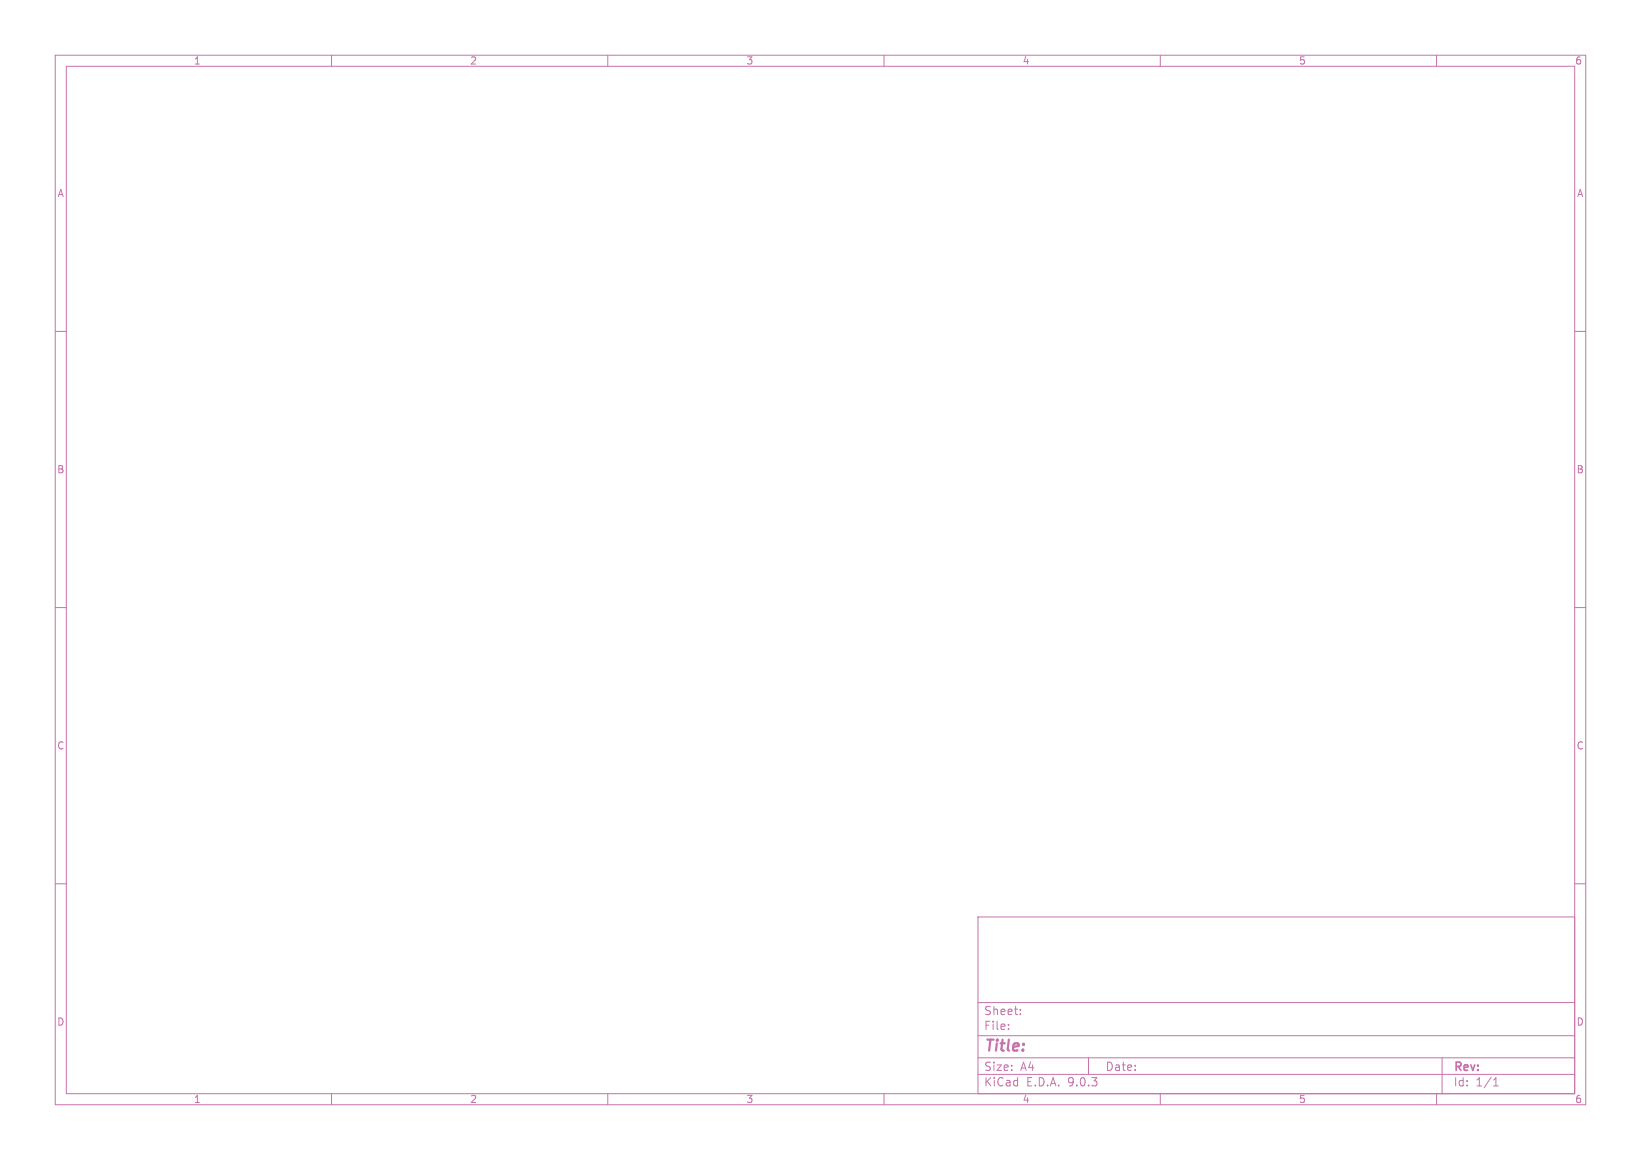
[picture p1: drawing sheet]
<svg xmlns="http://www.w3.org/2000/svg" width="297mm" height="210mm" viewBox="0 0 297 210" stroke-linecap="round" stroke-linejoin="round" font-family="sans-serif">
<defs><g id="words">
<text font-size="2.8" fill="#c872ab" x="178" y="190.9">Title:</text>
<g font-size="2.1" fill="#c872ab">
<text x="178" y="184">Sheet:</text>
<text x="178" y="186.7">File:</text>
<text x="178" y="196.9">KiCad</text>
<text x="178" y="194.1">Size:</text>
<text x="184.7" y="194.1">A4</text>
<text x="185.7" y="196.9">E.D.A.</text>
<text x="193.3" y="196.9">9.0.3</text>
<text x="200" y="194.1">Date:</text>
<text x="263" y="194.3">Rev:</text>
<text x="263" y="196.9">Id:</text>
<text x="267.1" y="196.9">1/1</text>
</g>
<g font-size="1.8" fill="#c872ab">
<text x="35" y="11.9">1</text>
<text x="85" y="11.9">2</text>
<text x="135" y="11.9">3</text>
<text x="185" y="11.9">4</text>
<text x="235" y="11.9">5</text>
<text x="285" y="11.9">6</text>
<text x="10.3" y="35.9">A</text>
<text x="285.4" y="35.9">A</text>
<text x="10.3" y="85.9">B</text>
<text x="285.3" y="85.9">B</text>
<text x="10.3" y="135.9">C</text>
<text x="285.3" y="135.9">C</text>
<text x="10.3" y="185.9">D</text>
<text x="285.3" y="185.9">D</text>
<text x="35" y="199.9">1</text>
<text x="85" y="199.9">2</text>
<text x="135" y="199.9">3</text>
<text x="185" y="199.9">4</text>
<text x="235" y="199.9">5</text>
<text x="285" y="199.9">6</text>
</g>
</g></defs>
<g fill="none" stroke="#c872ab" stroke-width=".18">
<path d="M10 10h277v190h-277zM12 12h273v186h-273zM60 10v2M110 10v2M160 10v2M210 10v2M260 10v2M10 60h2M285 60h2M10 110h2M285 110h2M10 160h2"/>
<path d="M177 166h108v32h-108zM285 160h2M60 198v2M110 198v2M160 198v2M177 194.5h108M177 191.5h108M177 187.5h108M177 181.5h108M182.5 186.3v.1M182.5 185.5v.1M184.7 183.6v.1"/>
<path d="M184.7 182.8v.1M197 191.5v3M210 198v2M260 198v2M261 191.5v6.5M270.3 196.6h.9M270.3 195.5l.4-.4v1.5"/>
</g>
<use href="#words"/>
</svg>
